VERSION 5.8 ;
BUSBITCHARS "[]" ;
DIVIDERCHAR "/" ;
UNITS
    DATABASE MICRONS 1000 ;
END UNITS

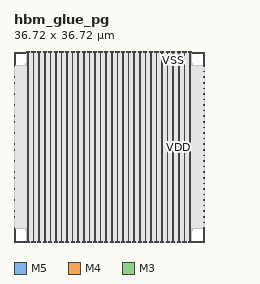
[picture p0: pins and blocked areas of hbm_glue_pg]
MACRO hbm_glue_pg
  FOREIGN hbm_glue_pg 0 0 ;
  CLASS BLOCK ;
  SIZE 36.72 BY 36.72 ;
  PIN ck
    DIRECTION INPUT ;
    USE SIGNAL ;
  END ck
  PIN co[0]
    DIRECTION OUTPUT ;
    USE SIGNAL ;
  END co[0]
  PIN co[1]
    DIRECTION OUTPUT ;
    USE SIGNAL ;
  END co[1]
  PIN co[2]
    DIRECTION OUTPUT ;
    USE SIGNAL ;
  END co[2]
  PIN co[3]
    DIRECTION OUTPUT ;
    USE SIGNAL ;
  END co[3]
  PIN ri[0]
    DIRECTION INPUT ;
    USE SIGNAL ;
  END ri[0]
  PIN ri[1]
    DIRECTION INPUT ;
    USE SIGNAL ;
  END ri[1]
  PIN ri[2]
    DIRECTION INPUT ;
    USE SIGNAL ;
  END ri[2]
  PIN ri[3]
    DIRECTION INPUT ;
    USE SIGNAL ;
  END ri[3]
  PIN ro[0]
    DIRECTION OUTPUT ;
    USE SIGNAL ;
  END ro[0]
  PIN ro[1]
    DIRECTION OUTPUT ;
    USE SIGNAL ;
  END ro[1]
  PIN ro[2]
    DIRECTION OUTPUT ;
    USE SIGNAL ;
  END ro[2]
  PIN ro[3]
    DIRECTION OUTPUT ;
    USE SIGNAL ;
  END ro[3]
  PIN VDD
    DIRECTION INOUT ;
    USE POWER ;
    PORT
      LAYER M5 ;
        RECT  33.96 36.696 34.08 36.72 ;
        RECT  33.96 0 34.08 0.024 ;
        RECT  33.96 0 34.08 36.72 ;
        RECT  31.8 36.696 31.92 36.72 ;
        RECT  31.8 0 31.92 0.024 ;
        RECT  31.8 0 31.92 36.72 ;
        RECT  29.64 36.696 29.76 36.72 ;
        RECT  29.64 0 29.76 0.024 ;
        RECT  29.64 0 29.76 36.72 ;
        RECT  27.48 36.696 27.6 36.72 ;
        RECT  27.48 0 27.6 0.024 ;
        RECT  27.48 0 27.6 36.72 ;
        RECT  25.32 36.696 25.44 36.72 ;
        RECT  25.32 0 25.44 0.024 ;
        RECT  25.32 0 25.44 36.72 ;
        RECT  23.16 36.696 23.28 36.72 ;
        RECT  23.16 0 23.28 0.024 ;
        RECT  23.16 0 23.28 36.72 ;
        RECT  21 36.696 21.12 36.72 ;
        RECT  21 0 21.12 0.024 ;
        RECT  21 0 21.12 36.72 ;
        RECT  18.84 36.696 18.96 36.72 ;
        RECT  18.84 0 18.96 0.024 ;
        RECT  18.84 0 18.96 36.72 ;
        RECT  16.68 36.696 16.8 36.72 ;
        RECT  16.68 0 16.8 0.024 ;
        RECT  16.68 0 16.8 36.72 ;
        RECT  14.52 36.696 14.64 36.72 ;
        RECT  14.52 0 14.64 0.024 ;
        RECT  14.52 0 14.64 36.72 ;
        RECT  12.36 36.696 12.48 36.72 ;
        RECT  12.36 0 12.48 0.024 ;
        RECT  12.36 0 12.48 36.72 ;
        RECT  10.2 36.696 10.32 36.72 ;
        RECT  10.2 0 10.32 0.024 ;
        RECT  10.2 0 10.32 36.72 ;
        RECT  8.04 36.696 8.16 36.72 ;
        RECT  8.04 0 8.16 0.024 ;
        RECT  8.04 0 8.16 36.72 ;
        RECT  5.88 36.696 6 36.72 ;
        RECT  5.88 0 6 0.024 ;
        RECT  5.88 0 6 36.72 ;
        RECT  3.72 36.696 3.84 36.72 ;
        RECT  3.72 0 3.84 0.024 ;
        RECT  3.72 0 3.84 36.72 ;
      LAYER M4 ;
        RECT  36.696 33.96 36.72 34.08 ;
        RECT  0 33.96 0.024 34.08 ;
        RECT  36.696 31.8 36.72 31.92 ;
        RECT  0 31.8 0.024 31.92 ;
        RECT  36.696 29.64 36.72 29.76 ;
        RECT  0 29.64 0.024 29.76 ;
        RECT  36.696 27.48 36.72 27.6 ;
        RECT  0 27.48 0.024 27.6 ;
        RECT  36.696 25.32 36.72 25.44 ;
        RECT  0 25.32 0.024 25.44 ;
        RECT  36.696 23.16 36.72 23.28 ;
        RECT  0 23.16 0.024 23.28 ;
        RECT  36.696 21 36.72 21.12 ;
        RECT  0 21 0.024 21.12 ;
        RECT  36.696 18.84 36.72 18.96 ;
        RECT  0 18.84 0.024 18.96 ;
        RECT  36.696 16.68 36.72 16.8 ;
        RECT  0 16.68 0.024 16.8 ;
        RECT  36.696 14.52 36.72 14.64 ;
        RECT  0 14.52 0.024 14.64 ;
        RECT  36.696 12.36 36.72 12.48 ;
        RECT  0 12.36 0.024 12.48 ;
        RECT  36.696 10.2 36.72 10.32 ;
        RECT  0 10.2 0.024 10.32 ;
        RECT  36.696 8.04 36.72 8.16 ;
        RECT  0 8.04 0.024 8.16 ;
        RECT  36.696 5.88 36.72 6 ;
        RECT  0 5.88 0.024 6 ;
        RECT  36.696 3.72 36.72 3.84 ;
        RECT  0 3.72 0.024 3.84 ;
      LAYER M3 ;
        RECT  34.245 36.702 34.335 36.72 ;
        RECT  34.245 0 34.335 0.018 ;
        RECT  33.165 36.702 33.255 36.72 ;
        RECT  33.165 0 33.255 0.018 ;
        RECT  32.085 36.702 32.175 36.72 ;
        RECT  32.085 0 32.175 0.018 ;
        RECT  31.005 36.702 31.095 36.72 ;
        RECT  31.005 0 31.095 0.018 ;
        RECT  29.925 36.702 30.015 36.72 ;
        RECT  29.925 0 30.015 0.018 ;
        RECT  28.845 36.702 28.935 36.72 ;
        RECT  28.845 0 28.935 0.018 ;
        RECT  27.765 36.702 27.855 36.72 ;
        RECT  27.765 0 27.855 0.018 ;
        RECT  26.685 36.702 26.775 36.72 ;
        RECT  26.685 0 26.775 0.018 ;
        RECT  25.605 36.702 25.695 36.72 ;
        RECT  25.605 0 25.695 0.018 ;
        RECT  24.525 36.702 24.615 36.72 ;
        RECT  24.525 0 24.615 0.018 ;
        RECT  23.445 36.702 23.535 36.72 ;
        RECT  23.445 0 23.535 0.018 ;
        RECT  22.365 36.702 22.455 36.72 ;
        RECT  22.365 0 22.455 0.018 ;
        RECT  21.285 36.702 21.375 36.72 ;
        RECT  21.285 0 21.375 0.018 ;
        RECT  20.205 36.702 20.295 36.72 ;
        RECT  20.205 0 20.295 0.018 ;
        RECT  19.125 36.702 19.215 36.72 ;
        RECT  19.125 0 19.215 0.018 ;
        RECT  18.045 36.702 18.135 36.72 ;
        RECT  18.045 0 18.135 0.018 ;
        RECT  16.965 36.702 17.055 36.72 ;
        RECT  16.965 0 17.055 0.018 ;
        RECT  15.885 36.702 15.975 36.72 ;
        RECT  15.885 0 15.975 0.018 ;
        RECT  14.805 36.702 14.895 36.72 ;
        RECT  14.805 0 14.895 0.018 ;
        RECT  13.725 36.702 13.815 36.72 ;
        RECT  13.725 0 13.815 0.018 ;
        RECT  12.645 36.702 12.735 36.72 ;
        RECT  12.645 0 12.735 0.018 ;
        RECT  11.565 36.702 11.655 36.72 ;
        RECT  11.565 0 11.655 0.018 ;
        RECT  10.485 36.702 10.575 36.72 ;
        RECT  10.485 0 10.575 0.018 ;
        RECT  9.405 36.702 9.495 36.72 ;
        RECT  9.405 0 9.495 0.018 ;
        RECT  8.325 36.702 8.415 36.72 ;
        RECT  8.325 0 8.415 0.018 ;
        RECT  7.245 36.702 7.335 36.72 ;
        RECT  7.245 0 7.335 0.018 ;
        RECT  6.165 36.702 6.255 36.72 ;
        RECT  6.165 0 6.255 0.018 ;
        RECT  5.085 36.702 5.175 36.72 ;
        RECT  5.085 0 5.175 0.018 ;
        RECT  4.005 36.702 4.095 36.72 ;
        RECT  4.005 0 4.095 0.018 ;
        RECT  2.925 36.702 3.015 36.72 ;
        RECT  2.925 0 3.015 0.018 ;
    END
  END VDD
  PIN VSS
    DIRECTION INOUT ;
    USE GROUND ;
    PORT
      LAYER M5 ;
        RECT  32.88 36.696 33 36.72 ;
        RECT  32.88 0 33 0.024 ;
        RECT  32.88 0 33 36.72 ;
        RECT  30.72 36.696 30.84 36.72 ;
        RECT  30.72 0 30.84 0.024 ;
        RECT  30.72 0 30.84 36.72 ;
        RECT  28.56 36.696 28.68 36.72 ;
        RECT  28.56 0 28.68 0.024 ;
        RECT  28.56 0 28.68 36.72 ;
        RECT  26.4 36.696 26.52 36.72 ;
        RECT  26.4 0 26.52 0.024 ;
        RECT  26.4 0 26.52 36.72 ;
        RECT  24.24 36.696 24.36 36.72 ;
        RECT  24.24 0 24.36 0.024 ;
        RECT  24.24 0 24.36 36.72 ;
        RECT  22.08 36.696 22.2 36.72 ;
        RECT  22.08 0 22.2 0.024 ;
        RECT  22.08 0 22.2 36.72 ;
        RECT  19.92 36.696 20.04 36.72 ;
        RECT  19.92 0 20.04 0.024 ;
        RECT  19.92 0 20.04 36.72 ;
        RECT  17.76 36.696 17.88 36.72 ;
        RECT  17.76 0 17.88 0.024 ;
        RECT  17.76 0 17.88 36.72 ;
        RECT  15.6 36.696 15.72 36.72 ;
        RECT  15.6 0 15.72 0.024 ;
        RECT  15.6 0 15.72 36.72 ;
        RECT  13.44 36.696 13.56 36.72 ;
        RECT  13.44 0 13.56 0.024 ;
        RECT  13.44 0 13.56 36.72 ;
        RECT  11.28 36.696 11.4 36.72 ;
        RECT  11.28 0 11.4 0.024 ;
        RECT  11.28 0 11.4 36.72 ;
        RECT  9.12 36.696 9.24 36.72 ;
        RECT  9.12 0 9.24 0.024 ;
        RECT  9.12 0 9.24 36.72 ;
        RECT  6.96 36.696 7.08 36.72 ;
        RECT  6.96 0 7.08 0.024 ;
        RECT  6.96 0 7.08 36.72 ;
        RECT  4.8 36.696 4.92 36.72 ;
        RECT  4.8 0 4.92 0.024 ;
        RECT  4.8 0 4.92 36.72 ;
        RECT  2.64 36.696 2.76 36.72 ;
        RECT  2.64 0 2.76 0.024 ;
        RECT  2.64 0 2.76 36.72 ;
      LAYER M4 ;
        RECT  36.696 32.88 36.72 33 ;
        RECT  0 32.88 0.024 33 ;
        RECT  36.696 30.72 36.72 30.84 ;
        RECT  0 30.72 0.024 30.84 ;
        RECT  36.696 28.56 36.72 28.68 ;
        RECT  0 28.56 0.024 28.68 ;
        RECT  36.696 26.4 36.72 26.52 ;
        RECT  0 26.4 0.024 26.52 ;
        RECT  36.696 24.24 36.72 24.36 ;
        RECT  0 24.24 0.024 24.36 ;
        RECT  36.696 22.08 36.72 22.2 ;
        RECT  0 22.08 0.024 22.2 ;
        RECT  36.696 19.92 36.72 20.04 ;
        RECT  0 19.92 0.024 20.04 ;
        RECT  36.696 17.76 36.72 17.88 ;
        RECT  0 17.76 0.024 17.88 ;
        RECT  36.696 15.6 36.72 15.72 ;
        RECT  0 15.6 0.024 15.72 ;
        RECT  36.696 13.44 36.72 13.56 ;
        RECT  0 13.44 0.024 13.56 ;
        RECT  36.696 11.28 36.72 11.4 ;
        RECT  0 11.28 0.024 11.4 ;
        RECT  36.696 9.12 36.72 9.24 ;
        RECT  0 9.12 0.024 9.24 ;
        RECT  36.696 6.96 36.72 7.08 ;
        RECT  0 6.96 0.024 7.08 ;
        RECT  36.696 4.8 36.72 4.92 ;
        RECT  0 4.8 0.024 4.92 ;
        RECT  36.696 2.64 36.72 2.76 ;
        RECT  0 2.64 0.024 2.76 ;
      LAYER M3 ;
        RECT  33.705 36.702 33.795 36.72 ;
        RECT  33.705 0 33.795 0.018 ;
        RECT  32.625 36.702 32.715 36.72 ;
        RECT  32.625 0 32.715 0.018 ;
        RECT  31.545 36.702 31.635 36.72 ;
        RECT  31.545 0 31.635 0.018 ;
        RECT  30.465 36.702 30.555 36.72 ;
        RECT  30.465 0 30.555 0.018 ;
        RECT  29.385 36.702 29.475 36.72 ;
        RECT  29.385 0 29.475 0.018 ;
        RECT  28.305 36.702 28.395 36.72 ;
        RECT  28.305 0 28.395 0.018 ;
        RECT  27.225 36.702 27.315 36.72 ;
        RECT  27.225 0 27.315 0.018 ;
        RECT  26.145 36.702 26.235 36.72 ;
        RECT  26.145 0 26.235 0.018 ;
        RECT  25.065 36.702 25.155 36.72 ;
        RECT  25.065 0 25.155 0.018 ;
        RECT  23.985 36.702 24.075 36.72 ;
        RECT  23.985 0 24.075 0.018 ;
        RECT  22.905 36.702 22.995 36.72 ;
        RECT  22.905 0 22.995 0.018 ;
        RECT  21.825 36.702 21.915 36.72 ;
        RECT  21.825 0 21.915 0.018 ;
        RECT  20.745 36.702 20.835 36.72 ;
        RECT  20.745 0 20.835 0.018 ;
        RECT  19.665 36.702 19.755 36.72 ;
        RECT  19.665 0 19.755 0.018 ;
        RECT  18.585 36.702 18.675 36.72 ;
        RECT  18.585 0 18.675 0.018 ;
        RECT  17.505 36.702 17.595 36.72 ;
        RECT  17.505 0 17.595 0.018 ;
        RECT  16.425 36.702 16.515 36.72 ;
        RECT  16.425 0 16.515 0.018 ;
        RECT  15.345 36.702 15.435 36.72 ;
        RECT  15.345 0 15.435 0.018 ;
        RECT  14.265 36.702 14.355 36.72 ;
        RECT  14.265 0 14.355 0.018 ;
        RECT  13.185 36.702 13.275 36.72 ;
        RECT  13.185 0 13.275 0.018 ;
        RECT  12.105 36.702 12.195 36.72 ;
        RECT  12.105 0 12.195 0.018 ;
        RECT  11.025 36.702 11.115 36.72 ;
        RECT  11.025 0 11.115 0.018 ;
        RECT  9.945 36.702 10.035 36.72 ;
        RECT  9.945 0 10.035 0.018 ;
        RECT  8.865 36.702 8.955 36.72 ;
        RECT  8.865 0 8.955 0.018 ;
        RECT  7.785 36.702 7.875 36.72 ;
        RECT  7.785 0 7.875 0.018 ;
        RECT  6.705 36.702 6.795 36.72 ;
        RECT  6.705 0 6.795 0.018 ;
        RECT  5.625 36.702 5.715 36.72 ;
        RECT  5.625 0 5.715 0.018 ;
        RECT  4.545 36.702 4.635 36.72 ;
        RECT  4.545 0 4.635 0.018 ;
        RECT  3.465 36.702 3.555 36.72 ;
        RECT  3.465 0 3.555 0.018 ;
        RECT  2.385 36.702 2.475 36.72 ;
        RECT  2.385 0 2.475 0.018 ;
    END
  END VSS
  OBS
    LAYER RVTN ;
     RECT  4.32 4.32 5.94 4.455 ;
     RECT  10.8 4.32 11.88 4.455 ;
     RECT  12.096 4.32 12.312 4.455 ;
     RECT  4.32 9.72 5.94 9.855 ;
     RECT  10.8 9.72 11.88 9.855 ;
     RECT  12.096 9.72 12.312 9.855 ;
     RECT  4.32 15.12 5.94 15.255 ;
     RECT  10.8 15.12 11.88 15.255 ;
     RECT  12.096 15.12 12.312 15.255 ;
     RECT  4.32 20.52 5.94 20.655 ;
     RECT  10.8 20.52 11.88 20.655 ;
     RECT  12.096 20.52 12.312 20.655 ;
    LAYER RVTP ;
     RECT  4.32 4.455 5.94 4.59 ;
     RECT  10.8 4.455 11.88 4.59 ;
     RECT  12.096 4.455 12.312 4.59 ;
     RECT  4.32 9.855 5.94 9.99 ;
     RECT  10.8 9.855 11.88 9.99 ;
     RECT  12.096 9.855 12.312 9.99 ;
     RECT  4.32 15.255 5.94 15.39 ;
     RECT  10.8 15.255 11.88 15.39 ;
     RECT  12.096 15.255 12.312 15.39 ;
     RECT  4.32 20.655 5.94 20.79 ;
     RECT  10.8 20.655 11.88 20.79 ;
     RECT  12.096 20.655 12.312 20.79 ;
    LAYER M1 ;
     RECT  2.16 2.151 34.56 34.569 ;
    LAYER M2 ;
     RECT  2.16 2.151 34.56 34.569 ;
    LAYER M3 ;
     RECT  2.385 0 34.335 36.72 ;
    LAYER M4 ;
     RECT  0 2.64 36.72 34.08 ;
    LAYER M5 ;
     RECT  2.64 0 34.08 36.72 ;
  END
END hbm_glue_pg
END LIBRARY
